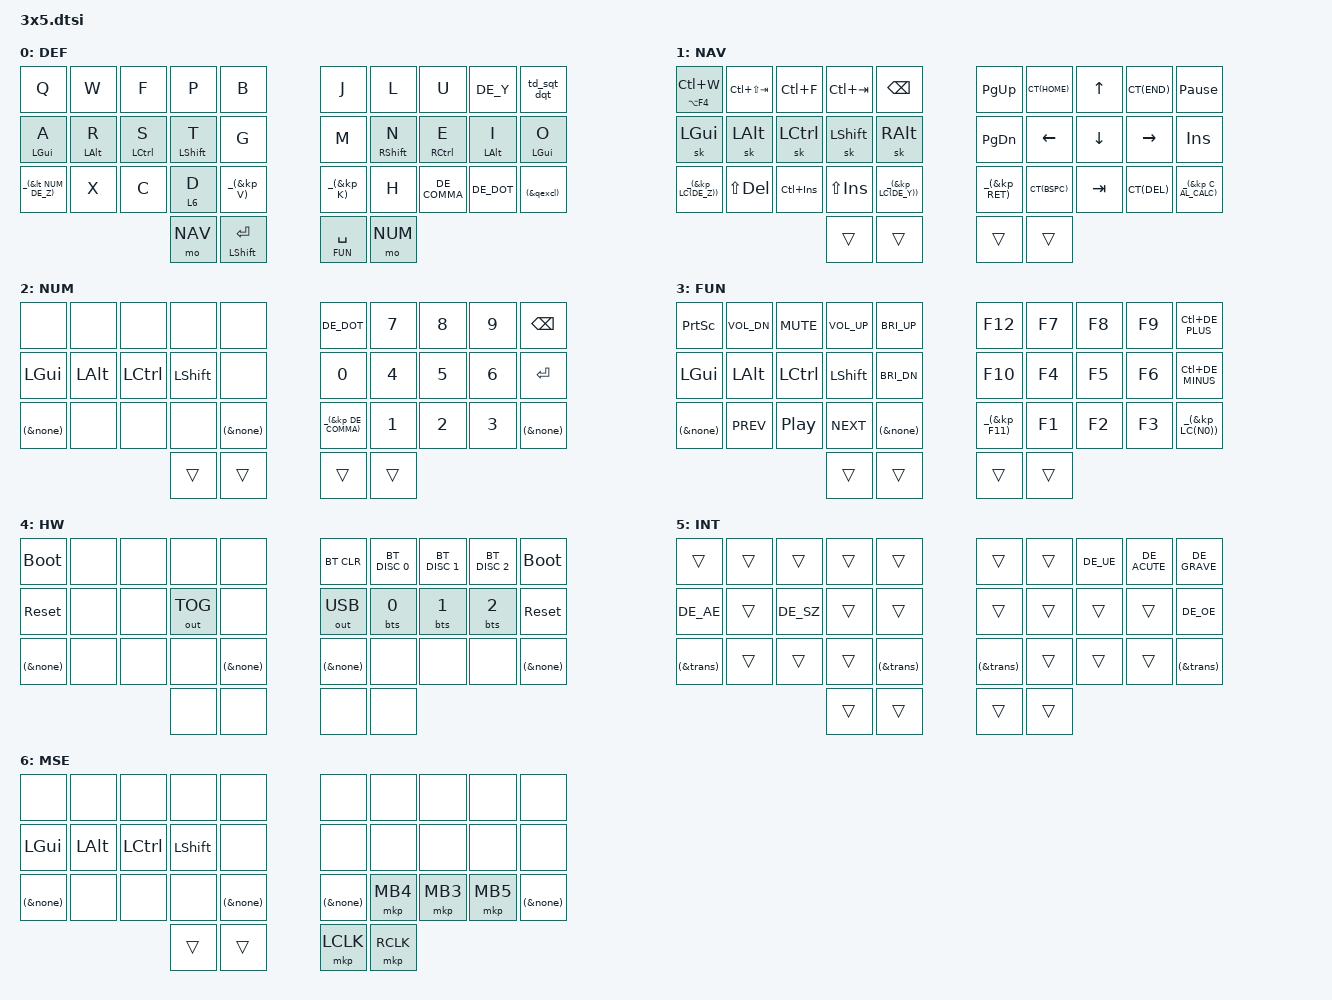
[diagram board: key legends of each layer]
/*
 * Copyright (c) 2020 The ZMK Contributors
 *
 * SPDX-License-Identifier: MIT
 */

#include <behaviors.dtsi>
#include <dt-bindings/zmk/mouse.h>
#include <dt-bindings/zmk/bt.h>
#include <dt-bindings/zmk/keys.h>
#include <dt-bindings/zmk/outputs.h>

#define DEF 0
#define NAV 1
#define NUM 2
#define FUN 3
#define HW  4
#define INT 5
#define MSE 6

#ifndef KEYMAP_DRAWER
#include "keys_de.h"
#endif

#include "keypos.h"
#include "combos.dtsi"

#define HM(NAME, TAP, HT_KEYPOS)                            \
    NAME: NAME {                                            \
        compatible = "zmk,behavior-hold-tap";               \
        #binding-cells = <2>;                               \
        flavor = "balanced";                                \
        tapping-term-ms = <280>;                            \
        quick-tap-ms = <175>;                               \
        require-prior-idle-ms = <175>;                      \
        bindings = <&kp>, <TAP>;                            \
        hold-trigger-key-positions = <HT_KEYPOS THUMBS>;    \
        hold-trigger-on-release;                            \
    };

#define SM(NAME, TAP, SHIFTED)                  \
    NAME: NAME {                                \
        compatible = "zmk,behavior-mod-morph";  \
        #binding-cells = <0>;                   \
        bindings = <TAP>, <SHIFTED>;            \
        mods = <(MOD_RSFT|MOD_LSFT)>;           \
    };
    
#define TD(NAME, T_TERM, TAP1, TAP2, ...)                                   \
    NAME: NAME {                                                            \
        compatible = "zmk,behavior-tap-dance";                              \
        #binding-cells = <0>;                                               \
        tapping-term-ms = <T_TERM>;                                         \
        bindings = <TAP1>, <TAP2> __VA_OPT__(, <)__VA_ARGS__ __VA_OPT__(>); \
    };

#if defined(KEYS_34)
    #define _(BINDING) BINDING 
#elif defined(KEYS_30)
    #define _(BINDING)
#endif

#define CT(KEY) &mt LC(KEY) KEY

&caps_word {
    continue-list = <BACKSPACE DELETE DE_UNDER DE_MINUS N0 N1 N2 N3 N4 N5 N6 N7 N8 N9>;
};

&sk {
    quick-release;
    release-after-ms = <900>;
};

&mt {
    quick-tap-ms = <220>;
    tapping-term-ms = <220>;
};

/ {
    behaviors {
        // home row mods
        HM(hml,         &kp,            KEYS_R)
        HM(hml_repeat,  &key_repeat,    KEYS_R)

        HM(hmr,             &kp,        KEYS_L)
        HM(hmr_lpar_lbrc,   &lpar_lbrc, KEYS_L)
        HM(hmr_rpar_rbrc,   &rpar_rbrc, KEYS_L)
        HM(hmr_par_brc,     &par_brc,   KEYS_L)

        // shift morphs
        SM(qexcl,           &kp DE_QMARK,   &kp DE_EXCL)

        SM(sqt_dqt,         &kp DE_SQT,     &kp DE_DQT)
        SM(sqt_dqt_macro,   &sqt_macro,     &dqt_macro)

        SM(lpar_lbrc,   &kp DE_LPAR,    &kp DE_LBRC)
        SM(rpar_rbrc,   &kp DE_RPAR,    &kp DE_RBRC)
        SM(par_brc,     &par_macro,     &brc_macro)

        SM(lbkt_lt, &kp DE_LBKT,    &kp DE_LT)
        SM(rbkt_gt, &kp DE_RBKT,    &kp DE_GT)
        SM(bkt_lgt, &bkt_macro,     &lgt_macro)

        // tap-dance
        TD(td_sqt_dqt,  270,    &sqt_dqt,   &sqt_dqt_macro)
    };

    macros {
        // ( ) <-
        ZMK_MACRO(par_macro,
            bindings = <&kp DE_LPAR &kp DE_RPAR &kp LEFT>;
        )
        
        // [ ] <-
        ZMK_MACRO(bkt_macro,
            bindings = <&kp DE_LBKT &kp DE_RBKT &kp LEFT>;
        )

        // ' ' <-
        ZMK_MACRO(sqt_macro,
            bindings = <&kp DE_SQT &kp DE_SQT &kp LEFT>;
        )

        // " " <-
        ZMK_MACRO(dqt_macro,
            bindings
                = <&macro_release &kp LSHFT>
                , <&macro_tap     &kp DE_DQT &kp DE_DQT &kp LEFT>;
        )

        // { } <-
        ZMK_MACRO(brc_macro,
            bindings
                = <&macro_release &kp LSHFT>
                , <&macro_tap     &kp DE_LBRC &kp DE_RBRC &kp LEFT>;
        )

        // < > <-
        ZMK_MACRO(lgt_macro,
            bindings
                = <&macro_release &kp LSHFT>
                , <&macro_tap     &kp DE_LT &kp DE_GT &kp LEFT>;
        )

        ZMK_MACRO1(bts,
            bindings
                = <&out OUT_BLE>
                , <&macro_param_1to2>
                , <&bt BT_SEL MACRO_PLACEHOLDER>;
        )
    };

    conditional_layers {
        compatible = "zmk,conditional-layers";

        tri_layer  {
            if-layers = <NAV NUM>;
            then-layer = <HW>;
        };
    };

    keymap {
        compatible = "zmk,keymap";

        default_layer {
            display-name = "DEF";
            bindings = <
// ╭───────────────┬─────────────┬─────────────┬─────────────┬─────────────╮   ╭─────────────┬─────────────┬─────────────┬─────────────┬─────────────╮
    &kp Q           &kp W         &kp F         &kp P         &kp B             &kp J         &kp L         &kp U         &kp DE_Y      &td_sqt_dqt
// ├───────────────┼─────────────┼─────────────┼─────────────┼─────────────┤   ├─────────────┼─────────────┼─────────────┼─────────────┼─────────────┤
    &hml LGUI A     &hml LALT R   &hml LCTRL S  &hml LSHIFT T &kp G             &kp M         &hmr RSHFT N  &hmr RCTRL E  &hmr LALT I   &hmr LGUI O
// ├───────────────┼─────────────┼─────────────┼─────────────┼─────────────┤   ├─────────────┼─────────────┼─────────────┼─────────────┼─────────────┤
    _(&lt NUM DE_Z) &kp X         &kp C         &lt 6 D       _(&kp V)          _(&kp K)      &kp H         &kp DE_COMMA  &kp DE_DOT    _(&qexcl)
// ╰───────────────┴─────────────┴─────────────┼─────────────┼─────────────┤   ├─────────────┼─────────────┼─────────────┴─────────────┴─────────────╯
                                                &mo NAV       &mt LSHFT RET     &lt FUN SPACE &mo NUM
//                                             ╰─────────────┴─────────────╯   ╰─────────────┴─────────────╯
            >;
        };

        navigation_layer {
            display-name = "NAV";
            bindings = <
// ╭────────────────┬────────────────┬─────────────┬─────────────┬───────────────╮   ╭─────────────┬─────────────┬─────────────┬─────────────┬────────────────╮
    &mt LA(F4) LC(W) &kp LC(LS(TAB))  &kp LC(F)     &kp LC(TAB)   &kp BSPC            &kp PG_UP     CT(HOME)      &kp UP        CT(END)       &kp PAUSE_BREAK
// ├────────────────┼────────────────┼─────────────┼─────────────┼───────────────┤   ├─────────────┼─────────────┼─────────────┼─────────────┼────────────────┤
    &sk LGUI         &sk LALT         &sk LCTRL     &sk LSHFT     &sk RALT            &kp PG_DN     &kp LEFT      &kp DOWN      &kp RIGHT     &kp INS
// ├────────────────┼────────────────┼─────────────┼─────────────┼───────────────┤   ├─────────────┼─────────────┼─────────────┼─────────────┼────────────────┤
    _(&kp LC(DE_Z))  &kp LS(DEL)      &kp LC(INS)   &kp LS(INS)   _(&kp LC(DE_Y))     _(&kp RET)    CT(BSPC)      &kp TAB       CT(DEL)       _(&kp C_AL_CALC)
// ╰────────────────┴────────────────┴─────────────┼─────────────┼───────────────┤   ├─────────────┼─────────────┼─────────────┴─────────────┴────────────────╯
                                                    &trans        &trans              &trans        &trans
//                                                 ╰─────────────┴───────────────╯   ╰─────────────┴─────────────╯
            >;
        };

        number_layer {
            display-name = "NUM";
            bindings = <
// ╭─────────────┬─────────────┬─────────────┬─────────────┬─────────────╮   ╭───────────────┬─────────────┬─────────────┬─────────────┬─────────────╮
    &none         &none         &none         &none         &none             &kp DE_DOT      &kp N7        &kp N8        &kp N9        &kp BSPC
// ├─────────────┼─────────────┼─────────────┼─────────────┼─────────────┤   ├───────────────┼─────────────┼─────────────┼─────────────┼─────────────┤
    &kp LGUI      &kp LALT      &kp LCTRL     &kp LSHFT     &none             &kp N0          &kp N4        &kp N5        &kp N6        &kp RET
// ├─────────────┼─────────────┼─────────────┼─────────────┼─────────────┤   ├───────────────┼─────────────┼─────────────┼─────────────┼─────────────┤
    _(&none)      &none         &none         &none         _(&none)          _(&kp DE_COMMA) &kp N1        &kp N2        &kp N3        _(&none)
// ╰─────────────┴─────────────┴─────────────┼─────────────┼─────────────┤   ├───────────────┼─────────────┼─────────────┴─────────────┴─────────────╯
                                              &trans        &trans            &trans          &trans
//                                           ╰─────────────┴─────────────╯   ╰───────────────┴─────────────╯
            >;
        };

        function_layer {
            display-name = "FUN";
            bindings = <
// ╭─────────────┬─────────────┬─────────────┬─────────────┬─────────────╮   ╭─────────────┬─────────────┬─────────────┬─────────────┬────────────────╮
    &kp PSCRN     &kp C_VOL_DN  &kp C_MUTE    &kp C_VOL_UP  &kp C_BRI_UP      &kp F12       &kp F7        &kp F8        &kp F9        &kp LC(DE_PLUS)
// ├─────────────┼─────────────┼─────────────┼─────────────┼─────────────┤   ├─────────────┼─────────────┼─────────────┼─────────────┼────────────────┤
    &kp LGUI      &kp LALT      &kp LCTRL     &kp LSHFT     &kp C_BRI_DN      &kp F10       &kp F4        &kp F5        &kp F6        &kp LC(DE_MINUS)
// ├─────────────┼─────────────┼─────────────┼─────────────┼─────────────┤   ├─────────────┼─────────────┼─────────────┼─────────────┼────────────────┤
    _(&none)      &kp C_PREV    &kp C_PP      &kp C_NEXT    _(&none)          _(&kp F11)    &kp F1        &kp F2        &kp F3        _(&kp LC(N0))
// ╰─────────────┴─────────────┴─────────────┼─────────────┼─────────────┤   ├─────────────┼─────────────┼─────────────┴─────────────┴────────────────╯
                                              &trans        &trans            &trans        &trans
//                                           ╰─────────────┴─────────────╯   ╰─────────────┴─────────────╯
            >;
        };

        hardware_layer {
            display-name = "HW";
            bindings = <
// ╭─────────────┬─────────────┬─────────────┬─────────────┬─────────────╮   ╭─────────────┬─────────────┬─────────────┬─────────────┬─────────────╮
    &bootloader   &none         &none         &none         &none             &bt BT_CLR    &bt BT_DISC 0 &bt BT_DISC 1 &bt BT_DISC 2 &bootloader
// ├─────────────┼─────────────┼─────────────┼─────────────┼─────────────┤   ├─────────────┼─────────────┼─────────────┼─────────────┼─────────────┤
    &sys_reset    &none         &none         &out OUT_TOG  &none             &out OUT_USB  &bts 0        &bts 1        &bts 2        &sys_reset
// ├─────────────┼─────────────┼─────────────┼─────────────┼─────────────┤   ├─────────────┼─────────────┼─────────────┼─────────────┼─────────────┤
    _(&none)      &none         &none         &none         _(&none)          _(&none)      &none         &none         &none         _(&none)
// ╰─────────────┴─────────────┴─────────────┼─────────────┼─────────────┤   ├─────────────┼─────────────┼─────────────┴─────────────┴─────────────╯
                                              &none         &none             &none         &none
//                                           ╰─────────────┴─────────────╯   ╰─────────────┴─────────────╯
            >;
        };

        international_layer {
            display-name = "INT";
            bindings = <
// ╭─────────────┬─────────────┬─────────────┬─────────────┬─────────────╮   ╭─────────────┬─────────────┬─────────────┬─────────────┬─────────────╮
    &trans        &trans        &trans        &trans        &trans            &trans        &trans        &kp DE_UE     &kp DE_ACUTE  &kp DE_GRAVE
// ├─────────────┼─────────────┼─────────────┼─────────────┼─────────────┤   ├─────────────┼─────────────┼─────────────┼─────────────┼─────────────┤
    &kp DE_AE     &trans        &kp DE_SZ     &trans        &trans            &trans        &trans        &trans        &trans        &kp DE_OE
// ├─────────────┼─────────────┼─────────────┼─────────────┼─────────────┤   ├─────────────┼─────────────┼─────────────┼─────────────┼─────────────┤
    _(&trans)     &trans        &trans        &trans        _(&trans)         _(&trans)     &trans        &trans        &trans        _(&trans)
// ╰─────────────┴─────────────┴─────────────┼─────────────┼─────────────┤   ├─────────────┼─────────────┼─────────────┴─────────────┴─────────────╯
                                              &trans        &trans            &trans        &trans
//                                           ╰─────────────┴─────────────╯   ╰─────────────┴─────────────╯
            >;
        };

        mouse_layer {
            display-name = "MSE";
            bindings = <
// ╭─────────────┬─────────────┬─────────────┬─────────────┬─────────────╮   ╭─────────────┬─────────────┬─────────────┬─────────────┬─────────────╮
    &none         &none         &none         &none         &none             &none         &none         &none         &none         &none
// ├─────────────┼─────────────┼─────────────┼─────────────┼─────────────┤   ├─────────────┼─────────────┼─────────────┼─────────────┼─────────────┤
    &kp LGUI      &kp LALT      &kp LCTRL     &kp LSHFT     &none             &none         &none         &none         &none         &none
// ├─────────────┼─────────────┼─────────────┼─────────────┼─────────────┤   ├─────────────┼─────────────┼─────────────┼─────────────┼─────────────┤
    _(&none)      &none         &none         &none         _(&none)          _(&none)      &mkp MB4      &mkp MB3      &mkp MB5      _(&none)
// ╰─────────────┴─────────────┴─────────────┼─────────────┼─────────────┤   ├─────────────┼─────────────┼─────────────┴─────────────┴─────────────╯
                                              &trans        &trans            &mkp LCLK     &mkp RCLK
//                                           ╰─────────────┴─────────────╯   ╰─────────────┴─────────────╯
            >;
        };
    };
};
